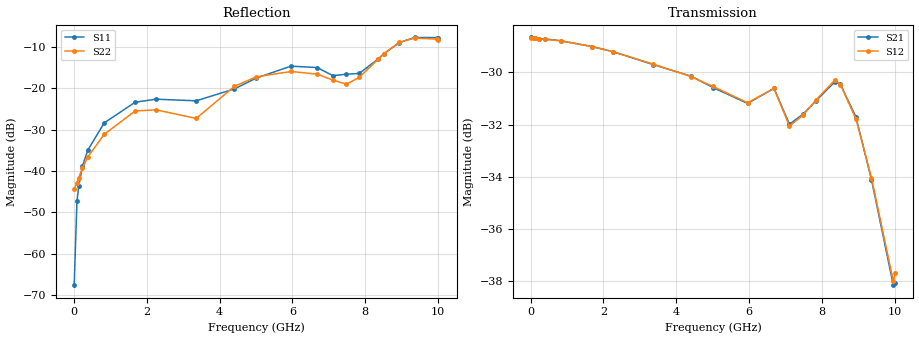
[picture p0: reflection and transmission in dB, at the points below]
! Device ID: PE43704
! Dir: z:\PE43704\PE43704_Char_1_20130516\PE43704\AMB\3p400V\27p75dB
! Serial: 14
! Insertion: A
! Impedance: 50 ohm
! Temp: Amb
! VDD: 3.400V
! Attenuation Step: 27.75dB
! IDD: 1.139634e-01mA
#  Hz  S  RI  R  50
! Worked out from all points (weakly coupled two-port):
!   401 points, 10 MHz to 10.01 GHz, reference 50 ohm
!   highest |S21| = -28.66 dB at 10 MHz (marker M1); lowest = -38.2 dB at 9.96 GHz (marker M2)
!   lowest |S11| = -67.6 dB at 10 MHz (marker M3), VSWR 1.00, Z = 50 + j0.0407 ohm
!   |S11| at or under -10 dB: start of sweep to 8.735 GHz
!   |S22| runs from -44.2 to -7.8 dB; largest |S21 - S12| = 0.00058
!   S11 on the Smith chart (normalised r, x): 10 MHz: 1.00, +0.00; 7.485 GHz: 0.78, +0.15; 8.51 GHz: 0.81, +0.45; 9.36 GHz: 0.54, +0.48; 10.01 GHz: 0.46, +0.27
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1e7  -9.89e-05 0.000407  0.0369 -9.71e-05  0.0368 -0.000135  0.00614 0.000389
8.5e7  -3.65e-05 0.00431  0.0368 -0.000815  0.0368 -0.00084  0.00629 0.00365
1.35e8  -0.000199 0.00663  0.0367 -0.00128  0.0367 -0.00127  0.00603 0.00575
2.35e8  -0.00185 0.0113  0.0366 -0.00218  0.0366 -0.00217  0.00459 0.00984
3.85e8  -0.00499 0.0173  0.0365 -0.00356  0.0364 -0.00351  0.00143 0.0148
8.35e8  -0.0251 0.0289  0.0356 -0.00732  0.0356 -0.00733  -0.0167 0.0223
1.685e9  -0.0664 0.015  0.0326 -0.0139  0.0326 -0.0139  -0.0533 0.00251
2.26e9  -0.074 -0.00226  0.0298 -0.0177  0.0298 -0.0177  -0.0535 -0.0127
3.36e9  -0.0707 -0.000819  0.0231 -0.0232  0.0232 -0.0232  -0.043 0.00524
4.41e9  -0.0885 0.0435  0.0172 -0.0259  0.0171 -0.0259  -0.0924 0.0519
5.01e9  -0.1121 0.072  0.0141 -0.026  0.0142 -0.0261  -0.1255 0.0571
5.96e9  -0.1595 0.0948  0.00888 -0.0261  0.00916 -0.0261  -0.1505 0.0542
6.685e9  -0.1593 0.0803  0.00669 -0.0287  0.00661 -0.0287  -0.1389 0.0529
7.11e9  -0.1287 0.0611  0.0017 -0.0251  0.00151 -0.0249  -0.106 0.068
7.485e9  -0.1152 0.0933  0.0024 -0.0262  0.00227 -0.0261  -0.0751 0.0837
7.835e9  -0.0722 0.1333  0.00204 -0.0278  0.00206 -0.0279  -0.059 0.122
8.36e9  -0.0406 0.2237  -0.00578 -0.0298  -0.00601 -0.03  -0.0732 0.2143
8.51e9  -0.044 0.2582  -0.00906 -0.0286  -0.00854 -0.0287  -0.0858 0.2488
8.935e9  -0.0964 0.3429  -0.0133 -0.0223  -0.0132 -0.0221  -0.1523 0.3263
9.36e9  -0.1878 0.3681  -0.0123 -0.0154  -0.0122 -0.0157  -0.2378 0.3284
9.96e9  -0.3166 0.2609  -0.00337 -0.0119  -0.00346 -0.0121  -0.3488 0.1833
1.001e10  -0.3243 0.2418  -0.00262 -0.0122  -0.00267 -0.0128  -0.3535 0.163
